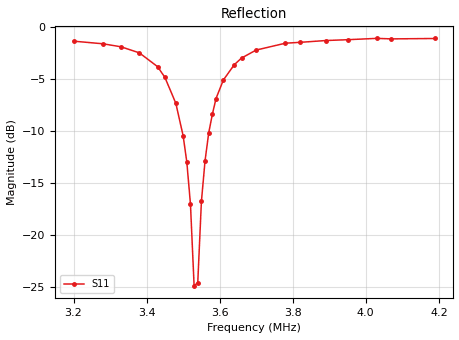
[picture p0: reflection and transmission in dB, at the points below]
! Touchstone file generated by AntScope (RigExpert AA-54 antenna analyzer)
# MHz Z RI R 50
! Format: Frequency Z-real Z-imaginary (normalized to 50 Ohm)
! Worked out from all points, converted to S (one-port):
!   100 points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, 3.2 MHz to 4.19 MHz, reference 50 ohm
!   lowest |S11| = -24.9 dB at 3.53 MHz (marker M1), VSWR 1.12, Z = 51.4 - j5.64 ohm
!   |S11| at or under -10 dB: 3.498 MHz to 3.571 MHz (73.34 kHz wide, 2.08 % of centre)
!   S11 on the Smith chart (normalised r, x): 3.2 MHz: 3.83, +5.86; 3.43 MHz: 1.06, -1.74; 3.54 MHz: 1.11, +0.06; 3.66 MHz: 5.26, -1.85; 3.89 MHz: 0.26, -1.58; 4.19 MHz: 0.09, -0.63
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3.2  3.835 5.865
3.28  9.593 -3.586
3.33  3.556 -4.436
3.38  1.66 -2.874
3.43  1.058 -1.742
3.45  0.9588 -1.373
3.48  0.9018 -0.9012
3.5  0.9104 -0.5946
3.51  0.9342 -0.442
3.52  0.9744 -0.281
3.53  1.028 -0.1128
3.54  1.107 0.064
3.55  1.213 0.2438
3.56  1.343 0.4216
3.57  1.529 0.611
3.58  1.763 0.7886
3.59  2.12 0.9742
3.61  3.002 1.184
3.64  4.88 0.2328
3.66  5.257 -1.845
3.7  2.787 -3.709
3.78  0.6836 -2.519
3.82  0.4584 -2.078
3.89  0.2602 -1.577
3.95  0.185 -1.288
4.03  0.1246 -1.007
4.07  0.1164 -0.8936
4.19  0.0868 -0.6254
